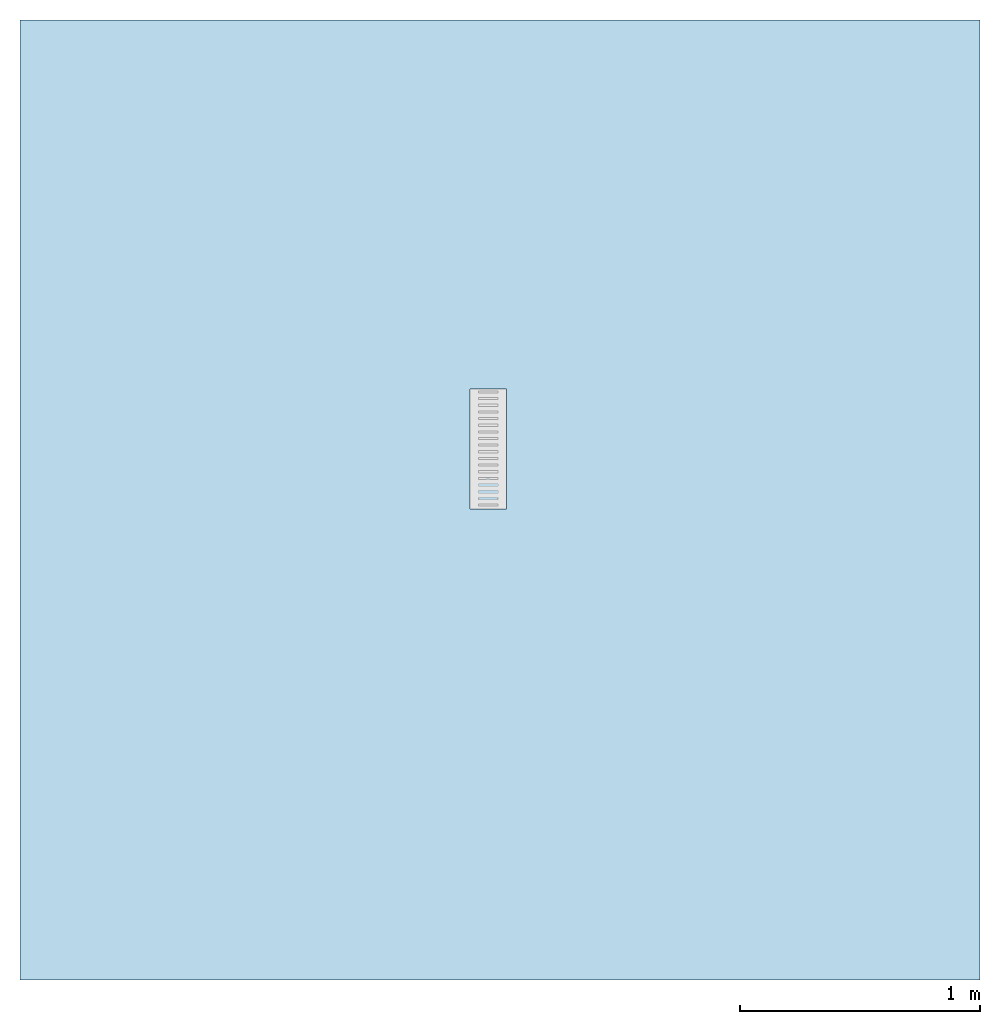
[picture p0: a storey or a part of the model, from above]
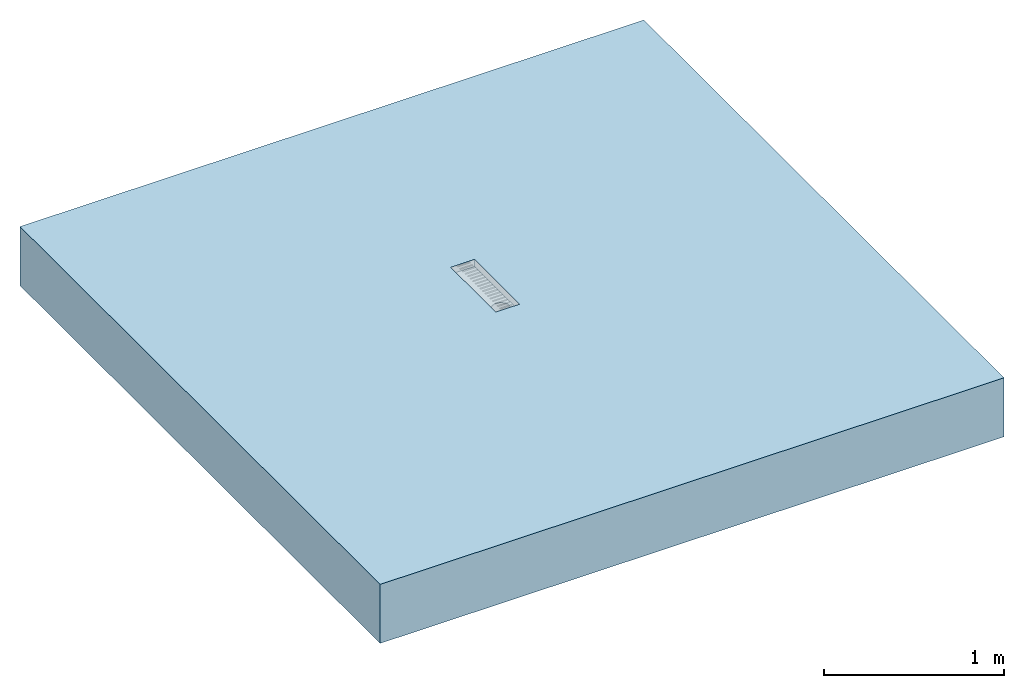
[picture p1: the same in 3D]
Properties of the parts of a building model (IFC2X3)

# File
Description: ViewDefinition [CoordinationView]
File name: 105263 - Level Outlet Invert Channel-500mm LG.ifc
Time: 2014-03-20T14:40:19
Written by: Autodesk Revit 2013
Made in: 20120221_2030(x64)

# IfcProject, Project Number
LongName: Project Name; Phase: Project Status

# IfcSite, Default
RefLatitude: 42, 21, 30, 344238; RefLongitude: -71, -3, -35, -194702; RefElevation: 0 mm

# IfcBuilding
Pset_BuildingCommon - NumberOfStoreys: 1
Other - Client Name: Owner; Project Status: Project Status; Project Name: Project Name; Project Number: Project Number; Project Address: ## Street City, State Zip; Project Issue Date: Issue Date

# IfcBuildingStorey, Level 1
LongName: Level 1; Elevation: 0 mm
Constraints - Elevation Base: 0; Elevation: 0 mm
Graphics - Symbol at End 1 Default: no; Symbol: M_Level Head - Circle: M_Level Head - Circle; Line Weight: 1; Symbol at End 2 Default: yes; Line Pattern: Center; Color: 0
Dimensions - Computation Height: 0 mm
Identity Data - Name: Level 1; Structural: no; Building Story: yes

# IfcBuildingElementProxy: 105263 - Level Outlet Invert Channel-500mm LG, ACO BD Deckline 125 Outlet Unit:105263 - Level Outlet Invert Channel-500mm LG:105263 - Level Outlet Invert Channel-500mm LG:222661
In: Level 1
Material: Steel, Galvanized
Model Properties - Grating Product Code 105525: Load Class C250 - Slotted Galvanized Steel - 500mm long - 2.3kg; Grating Product Code 105508: Load Class C250 - Perforated Galvanized Steel - 1000mm long - 4.8kg; Grating Product Code 105524: Load Class C250 - Slotted Galvanized Steel - 1000mm long - 4.7kg; Grating Product Code 105509: Load Class C250 - Perforated Galvanized Steel - 500mm long - 2.3kg; Grating Product Code 105523: Load Class A15 - Slotted Galvanized Steel - 500mm long - 1.0kg; Grating Product Code 10735: Load Class C250 - Composite White - 500mm long - 1.2kg; Grating Product Code 105522: Load Class A15 - Slotted Galvanized Steel - 1000mm long - 2.0kg; Grating Product Code 15704: Load Class C250 - Composite Black - 500mm long - 1.2kg
Construction - 105509 - C250 Perforated Grating - 500mm Long - Galvanized Finish.: no; End Plate Invert 1: no; End Plate Invert 2: no; 105525 - C250 Slotted Grating - 500mm Long - Galvanized Finish.: no; 105508 - C250 Perforated Grating - 1000mm Long - Galvanized Finish.: no; Foul Air Trap: no; 15704 - C250 Composite Grating - 500mm Long - Black Colored Finish.: no; Sieve: no; 105523 - A15 Slotted Grating - 500mm Long - Galvanized Finish.: no; 105522 - A15 Slotted Grating - 1000mm Long - Galvanized Finish.: no; 105524 - C250 Slotted Grating - 1000mm Long - Galvanized Finish.: no; 10735 - C250 Composite Grating - 500mm Long - White Colored Finish.: no
Phasing - Phase Created: New Construction
Dimensions - Volume: 1495885 mm3; Length Channel: -497 mm; Neoprene Gasket Start: -497 mm; Grating Void Cut Length: 500 mm; Endplate Position: 500 mm; Neoprene Gasket End: -500 mm
Constraints - Level: Level: Level 1
Pset_BuildingElementProxyCommon - Reference: 105263 - Level Outlet Invert Channel-500mm LG
Identity Data - Manufacturer: ACO Building Drainage; E-mail Sales: abdcommercial@aco.co.uk; Watermark2: This file is water marked and users are prohibited to reproduce, adapt, distribute this information.; E-mail Technical: abdtechnical@aco.co.uk; Fax: +44 (0)1462 851490; Website: www.acobd.com; Address: ACO Business Centre, Caxton Road, Bedford, MK41 0LF; Watermarked By: www.acobd.com; Watermarked With: BIM Manager Premium Suite.; Cost: 0; Telephone: +44 (0)1462 816666; Watermark1: This file is the property of ACO Technologies PLC.
General - Seal Material: Neoprene; Load Class: A15 - C250; Seal Colour: Black; Product Standard: BS EN 1433:2002 CE marked; Maintenance guidelines: X:\Electronic Literature\Building Drainage Literature\Deckline\Deckline 125.PDF; Channel Colour: Galvanized; Channel Recyclable: Fully recyclable; NBS Specification: NBS Section Q10 Kerbs/edgings/channels/paving accessories, Clause 180 Drainage Channel Systems; Channel Recycled Material Content: 25 - 30%; Seal Recycled Material Content: 0%; Weight (Kg): 2.6; Dimensions (LxWxH): 500mm x 153mm x 63mm; Product Type: shallow invert surface water drainage system; Price: POA - contact ACO; Seal Recyclable: Fully recyclable; Product Description: ACO Deckline Level Invert Channel Outlet (500 Long); Installation guidelines: X:\Electronic Literature\Building Drainage Literature\Deckline\Deckline 125.PDF; Product Code: 105263; Product Range: ACO Deckline 125; Channel Material: Hot Dipped Galvanized Steel

# IfcOpeningElement: Recess
In: Level 1
Constraints - Room Bounding: yes; Related to Mass: no; Height Offset From Level: 0 mm; Level: Level: Level 1
Phasing - Phase Created: New Construction
Dimensions - Perimeter: 16000 mm; Area: 16000000 mm2; Thickness: 400 mm; Volume: 6395278256 mm3
Structural - Enable Analytical Model: no; Structural: no
Analytical Properties - Absorptance: 0.1; Heat Transfer Coefficient (U): 2.615; Roughness: 1; Thermal mass: 604440; Thermal Resistance (R): 0.382409
Construction - Default Thickness: 400 mm; Function: 0
Graphics - Coarse Scale Fill Color: 0
Materials and Finishes - Structural Material: Concrete, Broom Finish

# IfcSlab: Floor:Generic Floor - 400mm, Floor:Generic Floor - 400mm:193825
In: Level 1
PredefinedType: FLOOR; Material: Concrete, Broom Finish 400 mm
Constraints - Room Bounding: yes; Related to Mass: no; Height Offset From Level: 0 mm; Level: Level: Level 1
Phasing - Phase Created: New Construction
Dimensions - Perimeter: 16000 mm; Area: 16000000 mm2; Thickness: 400 mm; Volume: 6395278256 mm3
Structural - Enable Analytical Model: no; Structural: no
Pset_SlabCommon - Reference: Generic Floor - 400mm; IsExternal: no; LoadBearing: yes
Analytical Properties - Absorptance: 0.1; Heat Transfer Coefficient (U): 2.615; Roughness: 1; Thermal mass: 604440; Thermal Resistance (R): 0.382409
Construction - Default Thickness: 400 mm; Function: 0
Graphics - Coarse Scale Fill Color: 0
Materials and Finishes - Structural Material: Concrete, Broom Finish
